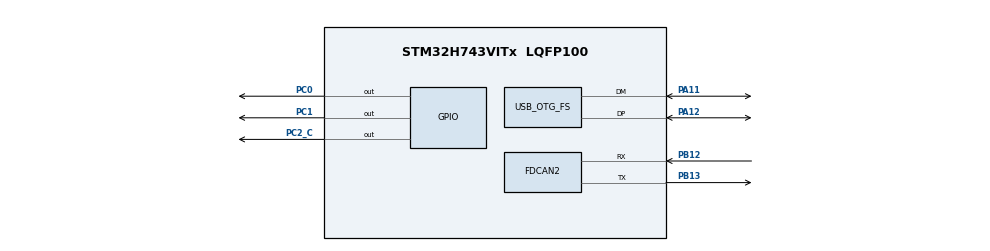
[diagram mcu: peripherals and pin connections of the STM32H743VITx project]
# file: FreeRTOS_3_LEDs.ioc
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Mcu.Family=STM32H7
Mcu.Name=STM32H743VITx
Mcu.Package=LQFP100
NVIC.FDCAN2_IT1_IRQn=true\:0\:0\:false\:false\:true\:true\:true\:true
NVIC.PriorityGroup=NVIC_PRIORITYGROUP_4
NVIC.TIM6_DAC_IRQn=true\:15\:0\:false\:false\:true\:false\:true\:true
NVIC.TimeBase=TIM6_DAC_IRQn
NVIC.TimeBaseIP=TIM6
PA11.Mode=Host_Only
PA11.Signal=USB_OTG_FS_DM
PA12.Mode=Host_Only
PA12.Signal=USB_OTG_FS_DP
PA13\ (JTMS/SWDIO).Mode=Trace_Asynchronous_SW
PA13\ (JTMS/SWDIO).Signal=DEBUG_JTMS-SWDIO
PA14\ (JTCK/SWCLK).Mode=Trace_Asynchronous_SW
PA14\ (JTCK/SWCLK).Signal=DEBUG_JTCK-SWCLK
PB12.Mode=FDCAN_Activate
PB12.Signal=FDCAN2_RX
PB13.Mode=FDCAN_Activate
PB13.Signal=FDCAN2_TX
PB3\ (JTDO/TRACESWO).Mode=Trace_Asynchronous_SW
PB3\ (JTDO/TRACESWO).Signal=DEBUG_JTDO-SWO
PC0.Signal=GPIO_Output
PC1.Signal=GPIO_Output
PC2_C.Signal=GPIO_Output
PH0-OSC_IN\ (PH0).Mode=HSE-External-Oscillator
PH0-OSC_IN\ (PH0).Signal=RCC_OSC_IN
PH1-OSC_OUT\ (PH1).Mode=HSE-External-Oscillator
PH1-OSC_OUT\ (PH1).Signal=RCC_OSC_OUT
ProjectManager.HeapSize=0x200
ProjectManager.StackSize=0x400
ProjectManager.TargetToolchain=STM32CubeIDE
RCC.ADCFreq_Value=16125000
RCC.APB1Freq_Value=4000000
RCC.APB2Freq_Value=8000000
RCC.APB3Freq_Value=8000000
RCC.APB4Freq_Value=8000000
RCC.CortexFreq_Value=8000000
RCC.D2PPRE1=RCC_APB1_DIV2
RCC.DIVM1=1
RCC.DIVN1=18
RCC.DIVQ1=3
RCC.HCLKFreq_Value=8000000
RCC.HSE_VALUE=8000000
RCC.PLL1_VCI_Range-AdvancedSettings=RCC_PLL1VCIRANGE_0
RCC.PLL2_VCI_Range-AdvancedSettings=RCC_PLL2VCIRANGE_0
RCC.PLL2_VCO_SEL-AdvancedSettings=RCC_PLL2VCOMEDIUM
RCC.PLL3_VCI_Range-AdvancedSettings=RCC_PLL3VCIRANGE_0
RCC.PLL3_VCO_SEL-AdvancedSettings=RCC_PLL3VCOMEDIUM
RCC.PLLFRACN=6144
RCC.SYSCLKFreq_VALUE=8000000
RCC.SYSCLKSource=RCC_SYSCLKSOURCE_HSE
RCC.USBFreq_Value=50000000
USB_OTG_FS.VirtualMode=Host_Only
USB_OTG_FS.phy_itface=HCD_PHY_EMBEDDED
VP_SYS_VS_tim6.Mode=TIM6
board=custom

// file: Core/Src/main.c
/* USER CODE BEGIN Header */
/**
  ******************************************************************************
  * @file           : main.c
  * @brief          : Main program body
  ******************************************************************************
  * @attention
  *
  * Copyright (c) 2021 STMicroelectronics.
  * All rights reserved.
  *
  * This software is licensed under terms that can be found in the LICENSE file
  * in the root directory of this software component.
  * If no LICENSE file comes with this software, it is provided AS-IS.
  *
  ******************************************************************************
  */
/* USER CODE END Header */
#include "main.h"

FDCAN_HandleTypeDef hfdcan2;

HCD_HandleTypeDef hhcd_USB_OTG_FS;

void SystemClock_Config(void);
static void MX_GPIO_Init(void);
static void MX_FDCAN2_Init(void);
static void MX_USB_OTG_FS_HCD_Init(void);
/* USER CODE BEGIN PFP */
extern void SEGGER_UART_init(U32 baud);
static void Task_GreenLED_Handler(void* parameters);
static void Task_RedLED_Handler(void* parameters);
static void Task_BlueLED_Handler(void* parameters);
/* USER CODE END PFP */

/* USER CODE BEGIN 0 */
char *user_data = "Hello world\r\n";
/* USER CODE END 0 */

int main(void)
{
  /* USER CODE BEGIN 1 */
	TaskHandle_t Task_GreenLED_Handle;
	TaskHandle_t Task_RedLED_Handle;
	TaskHandle_t Task_BlueLED_Handle;

	BaseType_t TaskStatus;

  /* USER CODE END 1 */

  /* MCU Configuration--------------------------------------------------------*/

  /* Reset of all peripherals, Initializes the Flash interface and the Systick. */
  HAL_Init();

  /* Configure the system clock */
  SystemClock_Config();

  /* Initialize all configured peripherals */
  MX_GPIO_Init();
  MX_FDCAN2_Init();
  MX_USB_OTG_FS_HCD_Init();
  /* USER CODE BEGIN 2 */

  // Start LED
  int Start_Counter = 0;
  while(Start_Counter < 5)
  {
	  HAL_GPIO_TogglePin(GPIOC, LED_Blue_PIN);
	  HAL_Delay(200);
	  HAL_GPIO_TogglePin(GPIOC, LED_Blue_PIN);
	  HAL_Delay(200);
	  Start_Counter++;
  }

//	user_data = "Start of program\r\n";
//	HAL_UART_Transmit(&huart2,(uint8_t*)user_data,strlen(user_data), HAL_MAX_DELAY);

	// Enable CCYCCNT Counter
	DWT->CTRL |= (1 << 0);

	// Used for SEGGER UART
	SEGGER_UART_init(500000);

	//Starting SEGGER SYSVIEW
	  SEGGER_SYSVIEW_Conf();
	  //SEGGER_SYSVIEW_Start();

	  TaskStatus = xTaskCreate(Task_GreenLED_Handler, "GreenLED", 100, "Green LED TASK", 1, &Task_GreenLED_Handle);
	  configASSERT(TaskStatus == pdPASS);

	  TaskStatus = xTaskCreate(Task_RedLED_Handler, "RedLED", 100, "Red LED TASK", 1, &Task_RedLED_Handle);
	  configASSERT(TaskStatus == pdPASS);

	  TaskStatus = xTaskCreate(Task_BlueLED_Handler, "BlueLED", 100, "Blue LED TASK", 1, &Task_BlueLED_Handle);
	  configASSERT(TaskStatus == pdPASS);

	  // Start FreeRTOS scheduler
	  vTaskStartScheduler();

//		user_data = "Scheduler called \r\n";
//		HAL_UART_Transmit(&huart2,(uint8_t*)user_data,strlen(user_data), HAL_MAX_DELAY);

  /* USER CODE END 2 */

  /* Infinite loop */
  while (1)
  {

  }
}

void SystemClock_Config(void)
{
  RCC_OscInitTypeDef RCC_OscInitStruct = {0};
  RCC_ClkInitTypeDef RCC_ClkInitStruct = {0};

  /** Supply configuration update enable
  */
  HAL_PWREx_ConfigSupply(PWR_LDO_SUPPLY);

  /** Configure the main internal regulator output voltage
  */
  __HAL_PWR_VOLTAGESCALING_CONFIG(PWR_REGULATOR_VOLTAGE_SCALE1);

  while(!__HAL_PWR_GET_FLAG(PWR_FLAG_VOSRDY)) {}

  __HAL_RCC_SYSCFG_CLK_ENABLE();
  __HAL_PWR_VOLTAGESCALING_CONFIG(PWR_REGULATOR_VOLTAGE_SCALE0);

  while(!__HAL_PWR_GET_FLAG(PWR_FLAG_VOSRDY)) {}

  /** Initializes the RCC Oscillators according to the specified parameters
  * in the RCC_OscInitTypeDef structure.
  */
  RCC_OscInitStruct.OscillatorType = RCC_OSCILLATORTYPE_HSE;
  RCC_OscInitStruct.HSEState = RCC_HSE_ON;
  RCC_OscInitStruct.PLL.PLLState = RCC_PLL_ON;
  RCC_OscInitStruct.PLL.PLLSource = RCC_PLLSOURCE_HSE;
  RCC_OscInitStruct.PLL.PLLM = 1;
  RCC_OscInitStruct.PLL.PLLN = 120;
  RCC_OscInitStruct.PLL.PLLP = 2;
  RCC_OscInitStruct.PLL.PLLQ = 15;
  RCC_OscInitStruct.PLL.PLLR = 2;
  RCC_OscInitStruct.PLL.PLLRGE = RCC_PLL1VCIRANGE_3;
  RCC_OscInitStruct.PLL.PLLVCOSEL = RCC_PLL1VCOWIDE;
  RCC_OscInitStruct.PLL.PLLFRACN = 0;
  if (HAL_RCC_OscConfig(&RCC_OscInitStruct) != HAL_OK)
  {
    Error_Handler();
  }

  /** Initializes the CPU, AHB and APB buses clocks
  */
  RCC_ClkInitStruct.ClockType = RCC_CLOCKTYPE_HCLK|RCC_CLOCKTYPE_SYSCLK
                              |RCC_CLOCKTYPE_PCLK1|RCC_CLOCKTYPE_PCLK2
                              |RCC_CLOCKTYPE_D3PCLK1|RCC_CLOCKTYPE_D1PCLK1;
  RCC_ClkInitStruct.SYSCLKSource = RCC_SYSCLKSOURCE_PLLCLK;
  RCC_ClkInitStruct.SYSCLKDivider = RCC_SYSCLK_DIV1;
  RCC_ClkInitStruct.AHBCLKDivider = RCC_HCLK_DIV2;
  RCC_ClkInitStruct.APB3CLKDivider = RCC_APB3_DIV2;
  RCC_ClkInitStruct.APB1CLKDivider = RCC_APB1_DIV2;
  RCC_ClkInitStruct.APB2CLKDivider = RCC_APB2_DIV2;
  RCC_ClkInitStruct.APB4CLKDivider = RCC_APB4_DIV2;

  if (HAL_RCC_ClockConfig(&RCC_ClkInitStruct, FLASH_LATENCY_4) != HAL_OK)
  {
    Error_Handler();
  }
}

static void MX_FDCAN2_Init(void)
{

  hfdcan2.Instance = FDCAN2;
  hfdcan2.Init.FrameFormat = FDCAN_FRAME_CLASSIC;
  hfdcan2.Init.Mode = FDCAN_MODE_NORMAL;
  hfdcan2.Init.AutoRetransmission = DISABLE;
  hfdcan2.Init.TransmitPause = DISABLE;
  hfdcan2.Init.ProtocolException = DISABLE;
  hfdcan2.Init.NominalPrescaler = 16;
  hfdcan2.Init.NominalSyncJumpWidth = 1;
  hfdcan2.Init.NominalTimeSeg1 = 2;
  hfdcan2.Init.NominalTimeSeg2 = 2;
  hfdcan2.Init.DataPrescaler = 1;
  hfdcan2.Init.DataSyncJumpWidth = 1;
  hfdcan2.Init.DataTimeSeg1 = 1;
  hfdcan2.Init.DataTimeSeg2 = 1;
  hfdcan2.Init.MessageRAMOffset = 0;
  hfdcan2.Init.StdFiltersNbr = 0;
  hfdcan2.Init.ExtFiltersNbr = 0;
  hfdcan2.Init.RxFifo0ElmtsNbr = 0;
  hfdcan2.Init.RxFifo0ElmtSize = FDCAN_DATA_BYTES_8;
  hfdcan2.Init.RxFifo1ElmtsNbr = 0;
  hfdcan2.Init.RxFifo1ElmtSize = FDCAN_DATA_BYTES_8;
  hfdcan2.Init.RxBuffersNbr = 0;
  hfdcan2.Init.RxBufferSize = FDCAN_DATA_BYTES_8;
  hfdcan2.Init.TxEventsNbr = 0;
  hfdcan2.Init.TxBuffersNbr = 0;
  hfdcan2.Init.TxFifoQueueElmtsNbr = 0;
  hfdcan2.Init.TxFifoQueueMode = FDCAN_TX_FIFO_OPERATION;
  hfdcan2.Init.TxElmtSize = FDCAN_DATA_BYTES_8;
  if (HAL_FDCAN_Init(&hfdcan2) != HAL_OK)
  {
    Error_Handler();
  }

}

static void MX_USB_OTG_FS_HCD_Init(void)
{

  hhcd_USB_OTG_FS.Instance = USB_OTG_FS;
  hhcd_USB_OTG_FS.Init.Host_channels = 16;
  hhcd_USB_OTG_FS.Init.speed = HCD_SPEED_FULL;
  hhcd_USB_OTG_FS.Init.dma_enable = DISABLE;
  hhcd_USB_OTG_FS.Init.phy_itface = HCD_PHY_EMBEDDED;
  hhcd_USB_OTG_FS.Init.Sof_enable = DISABLE;
  if (HAL_HCD_Init(&hhcd_USB_OTG_FS) != HAL_OK)
  {
    Error_Handler();
  }

}

static void MX_GPIO_Init(void)
{
  GPIO_InitTypeDef GPIO_InitStruct = {0};

  /* GPIO Ports Clock Enable */
  __HAL_RCC_GPIOC_CLK_ENABLE();
  __HAL_RCC_GPIOH_CLK_ENABLE();
  __HAL_RCC_GPIOB_CLK_ENABLE();
  __HAL_RCC_GPIOA_CLK_ENABLE();

  /*Configure GPIO pin Output Level */
  HAL_GPIO_WritePin(GPIOC, GPIO_PIN_0|GPIO_PIN_1|GPIO_PIN_2, GPIO_PIN_RESET);

  /*Configure GPIO pin : PC13 */
  GPIO_InitStruct.Pin = GPIO_PIN_13;
  GPIO_InitStruct.Mode = GPIO_MODE_IT_RISING;
  GPIO_InitStruct.Pull = GPIO_NOPULL;
  HAL_GPIO_Init(GPIOC, &GPIO_InitStruct);

  /*Configure GPIO pins : PC0 PC1 PC2 */
  GPIO_InitStruct.Pin = GPIO_PIN_0|GPIO_PIN_1|GPIO_PIN_2;
  GPIO_InitStruct.Mode = GPIO_MODE_OUTPUT_PP;
  GPIO_InitStruct.Pull = GPIO_NOPULL;
  GPIO_InitStruct.Speed = GPIO_SPEED_FREQ_LOW;
  HAL_GPIO_Init(GPIOC, &GPIO_InitStruct);

  /* EXTI interrupt init*/
  HAL_NVIC_SetPriority(EXTI15_10_IRQn, 5, 0);
  HAL_NVIC_EnableIRQ(EXTI15_10_IRQn);

}

/* USER CODE BEGIN 4 */
static void Task_GreenLED_Handler(void* parameters)
{
	TickType_t LastWakeUpTime = xTaskGetTickCount();
	while(1)
	{
//		user_data = "Green -\r\n";
//		HAL_UART_Transmit(&huart2,(uint8_t*)user_data,strlen(user_data), HAL_MAX_DELAY);
//		printf("%s\n", (char*)parameters);

		SEGGER_SYSVIEW_PrintfTarget("Toggling Green LED");

		// 1000 system tickes -> needs to be converted to ms
		HAL_GPIO_TogglePin(GPIOC, LED_Green_PIN);
		vTaskDelayUntil(&LastWakeUpTime, pdMS_TO_TICKS(1000));
		HAL_GPIO_TogglePin(GPIOC, LED_Green_PIN);
		vTaskDelayUntil(&LastWakeUpTime, pdMS_TO_TICKS(1000));
		taskYIELD();
	}
}

static void Task_RedLED_Handler(void* parameters)
{
	TickType_t LastWakeUpTime = xTaskGetTickCount();

	while(1)
	{
//		user_data = "Red -\r\n";
//		HAL_UART_Transmit(&huart2,(uint8_t*)user_data,strlen(user_data), HAL_MAX_DELAY);
//		printf("%s\n", (char*)parameters);

		SEGGER_SYSVIEW_PrintfTarget("Toggling Red LED");

		// 800 system tickes -> needs to be converted to ms
		HAL_GPIO_TogglePin(GPIOC, LED_Red_PIN);
		vTaskDelayUntil(&LastWakeUpTime, pdMS_TO_TICKS(800));
		HAL_GPIO_TogglePin(GPIOC, LED_Red_PIN);
		vTaskDelayUntil(&LastWakeUpTime, pdMS_TO_TICKS(800));
		taskYIELD();
	}
}

static void Task_BlueLED_Handler(void* parameters)
{
	TickType_t LastWakeUpTime = xTaskGetTickCount();

	while(1)
	{
//		user_data = "Blue -\r\n";
//		HAL_UART_Transmit(&huart2,(uint8_t*)user_data,strlen(user_data), HAL_MAX_DELAY);
//		printf("%s\n", (char*)parameters);

		SEGGER_SYSVIEW_PrintfTarget("Toggling Blue LED");

		// 400 system tickes -> needs to be converted to ms
		HAL_GPIO_TogglePin(GPIOC, LED_Blue_PIN);
		vTaskDelayUntil(&LastWakeUpTime, pdMS_TO_TICKS(400));
		HAL_GPIO_TogglePin(GPIOC, LED_Blue_PIN);
		vTaskDelayUntil(&LastWakeUpTime, pdMS_TO_TICKS(400));
		taskYIELD();
	}
}

/* USER CODE END 4 */

void HAL_TIM_PeriodElapsedCallback(TIM_HandleTypeDef *htim)
{
  if (htim->Instance == TIM6) {
    HAL_IncTick();
  }
}

void Error_Handler(void)
{
  /* USER CODE BEGIN Error_Handler_Debug */
  /* User can add his own implementation to report the HAL error return state */
  __disable_irq();
  while (1)
  {
		HAL_GPIO_TogglePin(GPIOC, LED_Red_PIN);
		HAL_Delay(100);
		HAL_GPIO_TogglePin(GPIOC, LED_Red_PIN);
		HAL_Delay(100);
  }
  /* USER CODE END Error_Handler_Debug */
}
